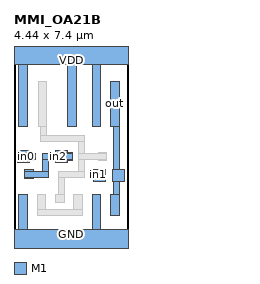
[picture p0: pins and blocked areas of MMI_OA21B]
MACRO MMI_OA21B
	CLASS CORE ;
	FOREIGN MMI_OA21B 0 0 ;
	SIZE 4.44 BY 7.4 ;
	SYMMETRY X Y ;
	SITE CORE1 ;
	PIN out
		DIRECTION output ;
		USE SIGNAL ;
		PORT
			LAYER M1 ;
			RECT 3.76 4.51 4.1 6.27 ;
			LAYER M1 ;
			RECT 3.87 2.815 4.1 4.51 ;
			LAYER M1 ;
			RECT 3.845 2.365 4.295 2.815 ;
			LAYER M1 ;
			RECT 3.87 1.86 4.1 2.365 ;
			LAYER M1 ;
			RECT 3.76 1.02 4.1 1.86 ;
		END
		AntennaDiffArea 1.3248 ;
	END out
	PIN in1
		DIRECTION input ;
		USE SIGNAL ;
		PORT
			LAYER M1 ;
			RECT 3.105 2.81 3.555 2.815 ;
			LAYER M1 ;
			RECT 2.98 2.47 3.555 2.81 ;
			LAYER M1 ;
			RECT 3.105 2.365 3.555 2.47 ;
		END
		AntennaGateArea 0.4968 ;
	END in1
	PIN GND
		DIRECTION inout ;
		USE GROUND ;
		PORT
			LAYER M1 ;
			RECT 0.18 0.5 0.52 1.86 ;
			LAYER M1 ;
			RECT 3.04 0.5 3.38 1.86 ;
			LAYER M1 ;
			RECT 0 -0.5 4.44 0.5 ;
		END
	END GND
	PIN in2
		DIRECTION input ;
		USE SIGNAL ;
		PORT
			LAYER M1 ;
			RECT 1.625 3.5 2.075 3.555 ;
			LAYER M1 ;
			RECT 1.625 3.445 2.29 3.5 ;
			LAYER M1 ;
			RECT 1.11 3.215 2.29 3.445 ;
			LAYER M1 ;
			RECT 0.42 2.755 0.76 2.81 ;
			LAYER M1 ;
			RECT 1.11 2.755 1.34 3.215 ;
			LAYER M1 ;
			RECT 1.625 3.16 2.29 3.215 ;
			LAYER M1 ;
			RECT 1.625 3.105 2.075 3.16 ;
			LAYER M1 ;
			RECT 0.42 2.525 1.34 2.755 ;
			LAYER M1 ;
			RECT 0.42 2.47 0.76 2.525 ;
		END
		AntennaGateArea 0.4968 ;
	END in2
	PIN VDD
		DIRECTION inout ;
		USE POWER ;
		PORT
			LAYER M1 ;
			RECT 0 6.9 4.44 7.9 ;
			LAYER M1 ;
			RECT 0.18 4.51 0.52 6.9 ;
			LAYER M1 ;
			RECT 2.09 4.51 2.43 6.9 ;
			LAYER M1 ;
			RECT 3.04 4.51 3.38 6.9 ;
		END
	END VDD
	PIN in0
		DIRECTION input ;
		USE SIGNAL ;
		PORT
			LAYER M1 ;
			RECT 0.145 3.5 0.595 3.555 ;
			LAYER M1 ;
			RECT 0.145 3.445 0.76 3.5 ;
			LAYER M1 ;
			RECT 0.145 3.215 0.825 3.445 ;
			LAYER M1 ;
			RECT 0.145 3.16 0.76 3.215 ;
			LAYER M1 ;
			RECT 0.145 3.105 0.595 3.16 ;
		END
		AntennaGateArea 0.3312 ;
	END in0
	OBS
		LAYER M1 ;
		RECT 0.94 4.51 1.28 6.27 ;
		LAYER M1 ;
		RECT 1.05 4.135 1.28 4.51 ;
		LAYER M1 ;
		RECT 1.05 3.905 2.75 4.135 ;
		LAYER M1 ;
		RECT 2.52 3.445 2.75 3.905 ;
		LAYER M1 ;
		RECT 3.28 3.445 3.62 3.5 ;
		LAYER M1 ;
		RECT 2.52 3.215 3.62 3.445 ;
		LAYER M1 ;
		RECT 2.52 2.755 2.75 3.215 ;
		LAYER M1 ;
		RECT 3.28 3.16 3.62 3.215 ;
		LAYER M1 ;
		RECT 1.73 2.525 2.75 2.755 ;
		LAYER M1 ;
		RECT 1.73 1.86 1.96 2.525 ;
		LAYER M1 ;
		RECT 0.9 1.25 1.24 1.86 ;
		LAYER M1 ;
		RECT 1.62 1.52 1.96 1.86 ;
		LAYER M1 ;
		RECT 2.32 1.25 2.66 1.86 ;
		LAYER M1 ;
		RECT 0.9 1.02 2.66 1.25 ;
	END
END MMI_OA21B
